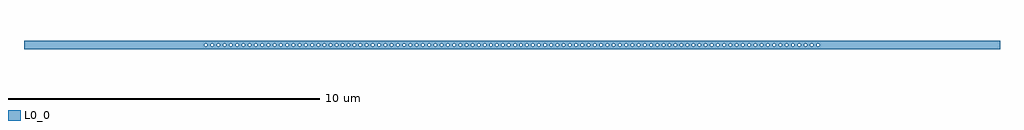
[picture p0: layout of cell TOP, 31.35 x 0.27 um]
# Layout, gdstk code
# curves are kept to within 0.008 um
import gdstk
lib = gdstk.Library(unit=1e-6, precision=1e-09)
def P(c, l, *ps):  # polygons
    for p in ps: c.add(gdstk.Polygon(p, *l))
L0_0 = (0, 0)

top = lib.new_cell('TOP')
P(top, L0_0, [(0,0),(0,0),(0,0),(0,0)],
  [(-8.211,0.048),(-8.197,0.041),(-8.184,0.03),(-8.177,0.016),(-8.175,0.005),(-8.175,0.133),(-15.675,0.133),(-15.675,0.049),(-8.228,0.049)],
  [(-8.175,-0.008),(-8.184,-0.03),(-8.211,-0.048),(-8.257,-0.036),(-8.272,-0.008),(-8.267,0.024),(-8.228,0.049),(-8.429,0.049),(-8.385,0.03),(-8.375,0),(-8.385,-0.03),(-8.429,-0.049),(-8.458,-0.036),(-8.473,-0.008),(-8.468,0.024),(-8.429,0.049),(-8.63,0.049),(-8.586,0.03),(-8.576,0),(-8.586,-0.03),(-8.63,-0.049),(-8.659,-0.036),(-8.674,-0.008),(-8.669,0.024),(-8.63,0.049),(-8.831,0.049),(-8.787,0.03),(-8.777,0),(-8.787,-0.03),(-8.831,-0.049),(-8.86,-0.036),(-8.875,-0.008),(-8.87,0.024),(-8.831,0.049),(-9.032,0.049),(-8.988,0.03),(-8.978,0),(-8.988,-0.03),(-9.032,-0.049),(-9.061,-0.036),(-9.076,-0.008),(-9.071,0.024),(-9.032,0.049),(-9.233,0.049),(-9.189,0.03),(-9.179,0),(-9.189,-0.03),(-9.233,-0.049),(-9.262,-0.036),(-9.277,-0.008),(-9.272,0.024),(-9.233,0.049),(-9.434,0.049),(-9.39,0.03),(-9.38,0),(-9.39,-0.03),(-9.434,-0.049),(-9.463,-0.036),(-9.478,-0.008),(-9.473,0.024),(-9.434,0.049),(-9.635,0.049),(-9.591,0.03),(-9.581,0),(-9.591,-0.03),(-9.635,-0.049),(-9.664,-0.036),(-9.679,-0.008),(-9.674,0.024),(-9.635,0.049),(-9.836,0.049),(-9.792,0.03),(-9.782,0),(-9.792,-0.03),(-9.836,-0.049),(-9.865,-0.036),(-9.88,-0.008),(-9.875,0.024),(-9.836,0.049),(-15.675,0.049),(-15.675,-0.133),(-8.175,-0.133)],
  [(-6.406,0.048),(-6.371,0.016),(-6.371,-0.016),(-6.391,-0.041),(-6.422,-0.049),(-6.451,-0.036),(-6.467,-0.008),(-6.461,0.024),(-6.422,0.049),(-6.622,0.049),(-6.578,0.03),(-6.568,0),(-6.578,-0.03),(-6.622,-0.049),(-6.65,-0.036),(-6.666,-0.008),(-6.66,0.024),(-6.622,0.049),(-6.822,0.049),(-6.778,0.03),(-6.768,0),(-6.778,-0.03),(-6.822,-0.049),(-6.851,-0.036),(-6.866,-0.008),(-6.861,0.024),(-6.822,0.049),(-7.022,0.049),(-6.979,0.03),(-6.969,0),(-6.979,-0.03),(-7.022,-0.049),(-7.051,-0.036),(-7.067,-0.008),(-7.061,0.024),(-7.022,0.049),(-7.223,0.049),(-7.18,0.03),(-7.17,0),(-7.18,-0.03),(-7.223,-0.049),(-7.252,-0.036),(-7.268,-0.008),(-7.262,0.024),(-7.223,0.049),(-7.424,0.049),(-7.381,0.03),(-7.371,0),(-7.381,-0.03),(-7.424,-0.049),(-7.453,-0.036),(-7.469,-0.008),(-7.463,0.024),(-7.424,0.049),(-7.625,0.049),(-7.581,0.03),(-7.571,0),(-7.581,-0.03),(-7.625,-0.049),(-7.654,-0.036),(-7.669,-0.008),(-7.664,0.024),(-7.625,0.049),(-7.826,0.049),(-7.782,0.03),(-7.772,0),(-7.782,-0.03),(-7.826,-0.049),(-7.855,-0.036),(-7.87,-0.008),(-7.865,0.024),(-7.826,0.049),(-8.027,0.049),(-7.983,0.03),(-7.973,0),(-7.983,-0.03),(-8.027,-0.049),(-8.056,-0.036),(-8.071,-0.008),(-8.066,0.024),(-8.027,0.049),(-8.175,0.049),(-8.175,-0.133),(-6.268,-0.133),(-6.268,0.133),(-8.175,0.133),(-8.175,0.049)],
  [(-6.253,0.036),(-6.239,0.046),(-6.224,0.049),(-6.268,0.049),(-6.268,0.008),(-6.263,0.024)],
  [(-6.268,0.133),(-6.268,0.049),(-4.675,0.049),(-4.632,0.03),(-4.622,0),(-4.644,-0.041),(-4.691,-0.046),(-4.714,-0.024),(-4.72,0.008),(-4.704,0.036),(-4.675,0.049),(-4.876,0.049),(-4.833,0.03),(-4.823,0),(-4.833,-0.03),(-4.876,-0.049),(-4.905,-0.036),(-4.921,-0.008),(-4.915,0.024),(-4.876,0.049),(-5.065,0.049),(-5.022,0.03),(-5.012,0),(-5.022,-0.03),(-5.065,-0.049),(-5.094,-0.036),(-5.11,-0.008),(-5.104,0.024),(-5.065,0.049),(-5.255,0.049),(-5.211,0.03),(-5.201,0),(-5.211,-0.03),(-5.255,-0.049),(-5.284,-0.036),(-5.299,-0.008),(-5.294,0.024),(-5.255,0.049),(-5.445,0.049),(-5.402,0.03),(-5.392,0),(-5.402,-0.03),(-5.445,-0.049),(-5.474,-0.036),(-5.49,-0.008),(-5.484,0.024),(-5.445,0.049),(-5.637,0.049),(-5.594,0.03),(-5.584,0),(-5.594,-0.03),(-5.637,-0.049),(-5.666,-0.036),(-5.682,-0.008),(-5.676,0.024),(-5.637,0.049),(-5.831,0.049),(-5.788,0.03),(-5.778,0),(-5.788,-0.03),(-5.831,-0.049),(-5.86,-0.036),(-5.876,-0.008),(-5.87,0.024),(-5.831,0.049),(-6.027,0.049),(-5.983,0.03),(-5.973,0),(-5.983,-0.03),(-6.027,-0.049),(-6.055,-0.036),(-6.071,-0.008),(-6.065,0.024),(-6.027,0.049),(-6.224,0.049),(-6.18,0.03),(-6.171,-0.008),(-6.193,-0.041),(-6.224,-0.049),(-6.253,-0.036),(-6.268,-0.008),(-6.268,-0.133),(-4.503,-0.133),(-4.503,-0.036),(-4.519,-0.008),(-4.503,0.036),(-4.503,0.133)],
  [(-2.649,0.048),(-2.649,0.133),(-4.503,0.133),(-4.503,0.049),(-2.665,0.049)],
  [(-2.649,-0.048),(-2.681,-0.046),(-2.71,-0.008),(-2.704,0.024),(-2.665,0.049),(-2.866,0.049),(-2.823,0.03),(-2.813,0),(-2.823,-0.03),(-2.866,-0.049),(-2.895,-0.036),(-2.911,-0.008),(-2.905,0.024),(-2.866,0.049),(-3.067,0.049),(-3.024,0.03),(-3.014,0),(-3.024,-0.03),(-3.067,-0.049),(-3.096,-0.036),(-3.112,-0.008),(-3.106,0.024),(-3.067,0.049),(-3.268,0.049),(-3.225,0.03),(-3.215,0),(-3.225,-0.03),(-3.268,-0.049),(-3.297,-0.036),(-3.313,-0.008),(-3.307,0.024),(-3.268,0.049),(-3.469,0.049),(-3.426,0.03),(-3.416,0),(-3.426,-0.03),(-3.469,-0.049),(-3.498,-0.036),(-3.514,-0.008),(-3.508,0.024),(-3.469,0.049),(-3.67,0.049),(-3.627,0.03),(-3.617,0),(-3.627,-0.03),(-3.67,-0.049),(-3.699,-0.036),(-3.715,-0.008),(-3.709,0.024),(-3.67,0.049),(-3.871,0.049),(-3.828,0.03),(-3.818,0),(-3.828,-0.03),(-3.871,-0.049),(-3.9,-0.036),(-3.916,-0.008),(-3.91,0.024),(-3.871,0.049),(-4.072,0.049),(-4.029,0.03),(-4.019,0),(-4.029,-0.03),(-4.072,-0.049),(-4.101,-0.036),(-4.117,-0.008),(-4.111,0.024),(-4.072,0.049),(-4.273,0.049),(-4.23,0.03),(-4.22,0),(-4.23,-0.03),(-4.273,-0.049),(-4.302,-0.036),(-4.318,-0.008),(-4.312,0.024),(-4.273,0.049),(-4.474,0.049),(-4.431,0.03),(-4.423,-0.016),(-4.458,-0.048),(-4.503,-0.036),(-4.503,-0.133),(-2.649,-0.133)],
  [(-4.49,0.046),(-4.474,0.049),(-4.503,0.049),(-4.503,0.036)],
  [(-0.855,0.048),(-0.841,0.041),(-0.841,0.133),(-2.649,0.133),(-2.649,0.049),(-0.871,0.049)],
  [(-0.841,-0.041),(-0.887,-0.046),(-0.916,-0.008),(-0.91,0.024),(-0.871,0.049),(-1.067,0.049),(-1.024,0.03),(-1.014,0),(-1.024,-0.03),(-1.067,-0.049),(-1.096,-0.036),(-1.112,-0.008),(-1.106,0.024),(-1.067,0.049),(-1.264,0.049),(-1.221,0.03),(-1.211,0),(-1.221,-0.03),(-1.264,-0.049),(-1.293,-0.036),(-1.309,-0.008),(-1.303,0.024),(-1.264,0.049),(-1.463,0.049),(-1.419,0.03),(-1.409,0),(-1.419,-0.03),(-1.463,-0.049),(-1.492,-0.036),(-1.507,-0.008),(-1.502,0.024),(-1.463,0.049),(-1.662,0.049),(-1.619,0.03),(-1.609,0),(-1.619,-0.03),(-1.662,-0.049),(-1.691,-0.036),(-1.707,-0.008),(-1.701,0.024),(-1.662,0.049),(-1.862,0.049),(-1.819,0.03),(-1.809,0),(-1.819,-0.03),(-1.862,-0.049),(-1.891,-0.036),(-1.907,-0.008),(-1.901,0.024),(-1.862,0.049),(-2.063,0.049),(-2.019,0.03),(-2.009,0),(-2.019,-0.03),(-2.063,-0.049),(-2.092,-0.036),(-2.107,-0.008),(-2.102,0.024),(-2.063,0.049),(-2.264,0.049),(-2.22,0.03),(-2.21,0),(-2.22,-0.03),(-2.264,-0.049),(-2.292,-0.036),(-2.308,-0.008),(-2.302,0.024),(-2.264,0.049),(-2.464,0.049),(-2.421,0.03),(-2.411,0),(-2.421,-0.03),(-2.464,-0.049),(-2.493,-0.036),(-2.509,-0.008),(-2.503,0.024),(-2.464,0.049),(-2.649,0.049),(-2.622,0.03),(-2.612,0),(-2.622,-0.03),(-2.649,-0.048),(-2.649,-0.133),(-0.841,-0.133)],
  [(0.879,0.048),(0.894,0.041),(0.894,0.133),(-0.841,0.133),(-0.841,0.049),(0.863,0.049)],
  [(0.894,-0.041),(0.847,-0.046),(0.818,-0.008),(0.824,0.024),(0.863,0.049),(0.669,0.049),(0.712,0.03),(0.722,0),(0.712,-0.03),(0.669,-0.049),(0.64,-0.036),(0.624,-0.008),(0.63,0.024),(0.669,0.049),(0.477,0.049),(0.52,0.03),(0.53,0),(0.52,-0.03),(0.477,-0.049),(0.448,-0.036),(0.432,-0.008),(0.438,0.024),(0.477,0.049),(0.287,0.049),(0.33,0.03),(0.34,0),(0.33,-0.03),(0.287,-0.049),(0.258,-0.036),(0.242,-0.008),(0.248,0.024),(0.287,0.049),(0.097,0.049),(0.128,0.041),(0.151,0),(0.128,-0.041),(0.097,-0.049),(0.068,-0.036),(0.052,-0.008),(0.058,0.024),(0.097,0.049),(-0.106,0.049),(-0.062,0.03),(-0.052,0),(-0.062,-0.03),(-0.106,-0.049),(-0.135,-0.036),(-0.151,-0.008),(-0.145,0.024),(-0.106,0.049),(-0.295,0.049),(-0.252,0.03),(-0.242,0),(-0.252,-0.03),(-0.295,-0.049),(-0.324,-0.036),(-0.34,-0.008),(-0.334,0.024),(-0.295,0.049),(-0.486,0.049),(-0.442,0.03),(-0.432,0),(-0.442,-0.03),(-0.486,-0.049),(-0.514,-0.036),(-0.53,-0.008),(-0.524,0.024),(-0.486,0.049),(-0.678,0.049),(-0.634,0.03),(-0.624,0),(-0.634,-0.03),(-0.678,-0.049),(-0.706,-0.036),(-0.722,-0.008),(-0.716,0.024),(-0.678,0.049),(-0.841,0.049),(-0.818,0),(-0.841,-0.041),(-0.841,-0.133),(0.894,-0.133)],
  [(2.673,0.048),(2.688,0.041),(2.7,0.03),(2.7,0.133),(0.894,0.133),(0.894,0.049),(2.657,0.049)],
  [(2.7,-0.03),(2.657,-0.049),(2.618,-0.024),(2.618,0.024),(2.657,0.049),(2.456,0.049),(2.499,0.03),(2.509,0),(2.499,-0.03),(2.456,-0.049),(2.427,-0.036),(2.411,-0.008),(2.417,0.024),(2.456,0.049),(2.255,0.049),(2.298,0.03),(2.308,0),(2.298,-0.03),(2.255,-0.049),(2.226,-0.036),(2.21,-0.008),(2.216,0.024),(2.255,0.049),(2.054,0.049),(2.097,0.03),(2.107,0),(2.097,-0.03),(2.054,-0.049),(2.025,-0.036),(2.009,-0.008),(2.015,0.024),(2.054,0.049),(1.854,0.049),(1.897,0.03),(1.907,0),(1.897,-0.03),(1.854,-0.049),(1.825,-0.036),(1.809,-0.008),(1.815,0.024),(1.854,0.049),(1.653,0.049),(1.697,0.03),(1.707,0),(1.697,-0.03),(1.653,-0.049),(1.625,-0.036),(1.609,-0.008),(1.615,0.024),(1.653,0.049),(1.454,0.049),(1.497,0.03),(1.507,0),(1.497,-0.03),(1.454,-0.049),(1.425,-0.036),(1.409,-0.008),(1.415,0.024),(1.454,0.049),(1.256,0.049),(1.299,0.03),(1.309,0),(1.299,-0.03),(1.256,-0.049),(1.227,-0.036),(1.211,-0.008),(1.217,0.024),(1.256,0.049),(1.058,0.049),(1.102,0.03),(1.112,0),(1.102,-0.03),(1.058,-0.049),(1.03,-0.036),(1.014,-0.008),(1.02,0.024),(1.058,0.049),(0.894,0.049),(0.916,0),(0.894,-0.041),(0.894,-0.133),(2.7,-0.133)],
  [(4.281,0.048),(4.308,0.03),(4.318,0),(4.308,-0.03),(4.265,-0.049),(4.236,-0.036),(4.22,-0.008),(4.226,0.024),(4.265,0.049),(4.064,0.049),(4.107,0.03),(4.117,0),(4.107,-0.03),(4.064,-0.049),(4.035,-0.036),(4.019,-0.008),(4.025,0.024),(4.064,0.049),(3.863,0.049),(3.906,0.03),(3.916,0),(3.906,-0.03),(3.863,-0.049),(3.834,-0.036),(3.818,-0.008),(3.824,0.024),(3.863,0.049),(3.662,0.049),(3.705,0.03),(3.715,0),(3.705,-0.03),(3.662,-0.049),(3.633,-0.036),(3.617,-0.008),(3.623,0.024),(3.662,0.049),(3.461,0.049),(3.504,0.03),(3.514,0),(3.504,-0.03),(3.461,-0.049),(3.432,-0.036),(3.416,-0.008),(3.422,0.024),(3.461,0.049),(3.26,0.049),(3.303,0.03),(3.313,0),(3.303,-0.03),(3.26,-0.049),(3.231,-0.036),(3.215,-0.008),(3.221,0.024),(3.26,0.049),(3.059,0.049),(3.102,0.03),(3.112,0),(3.102,-0.03),(3.059,-0.049),(3.03,-0.036),(3.014,-0.008),(3.02,0.024),(3.059,0.049),(2.858,0.049),(2.901,0.03),(2.911,0),(2.901,-0.03),(2.858,-0.049),(2.829,-0.036),(2.813,-0.008),(2.819,0.024),(2.858,0.049),(2.7,0.049),(2.71,0),(2.7,-0.133),(4.466,-0.133),(4.466,-0.049),(4.437,-0.036),(4.421,-0.008),(4.427,0.024),(4.466,0.049),(4.466,0.133),(2.7,0.133),(2.7,0.049)],
  [(6.034,0.048),(6.069,0.016),(6.069,-0.016),(6.049,-0.041),(6.018,-0.049),(5.989,-0.036),(5.973,-0.008),(5.979,0.024),(6.018,0.049),(5.822,0.049),(5.866,0.03),(5.876,0),(5.866,-0.03),(5.822,-0.049),(5.793,-0.036),(5.777,-0.008),(5.783,0.024),(5.822,0.049),(5.628,0.049),(5.672,0.03),(5.682,0),(5.672,-0.03),(5.628,-0.049),(5.6,-0.036),(5.584,-0.008),(5.59,0.024),(5.628,0.049),(5.436,0.049),(5.48,0.03),(5.49,0),(5.48,-0.03),(5.436,-0.049),(5.408,-0.036),(5.392,-0.008),(5.398,0.024),(5.436,0.049),(5.246,0.049),(5.289,0.03),(5.299,0),(5.289,-0.03),(5.246,-0.049),(5.217,-0.036),(5.201,-0.008),(5.207,0.024),(5.246,0.049),(5.057,0.049),(5.1,0.03),(5.11,0),(5.1,-0.03),(5.057,-0.049),(5.028,-0.036),(5.012,-0.008),(5.018,0.024),(5.057,0.049),(4.868,0.049),(4.911,0.03),(4.921,0),(4.911,-0.03),(4.868,-0.049),(4.839,-0.036),(4.823,-0.008),(4.829,0.024),(4.868,0.049),(4.667,0.049),(4.71,0.03),(4.72,0),(4.71,-0.03),(4.667,-0.049),(4.638,-0.036),(4.622,-0.008),(4.628,0.024),(4.667,0.049),(4.466,0.049),(4.509,0.03),(4.519,0),(4.509,-0.03),(4.466,-0.049),(4.466,-0.133),(6.215,-0.133),(6.215,-0.049),(6.186,-0.036),(6.17,-0.008),(6.176,0.024),(6.215,0.049),(6.215,0.133),(4.466,0.133),(4.466,0.049)],
  [(8.034,0.048),(8.034,0.133),(6.215,0.133),(6.215,0.049),(8.018,0.049)],
  [(8.034,-0.048),(8.002,-0.046),(7.973,-0.008),(7.979,0.024),(8.018,0.049),(7.817,0.049),(7.86,0.03),(7.87,0),(7.86,-0.03),(7.817,-0.049),(7.788,-0.036),(7.772,-0.008),(7.778,0.024),(7.817,0.049),(7.616,0.049),(7.659,0.03),(7.669,0),(7.659,-0.03),(7.616,-0.049),(7.587,-0.036),(7.571,-0.008),(7.577,0.024),(7.616,0.049),(7.415,0.049),(7.446,0.041),(7.469,0),(7.446,-0.041),(7.415,-0.049),(7.386,-0.036),(7.37,-0.008),(7.376,0.024),(7.415,0.049),(7.214,0.049),(7.258,0.03),(7.268,0),(7.258,-0.03),(7.214,-0.049),(7.185,-0.036),(7.17,-0.008),(7.175,0.024),(7.214,0.049),(7.014,0.049),(7.057,0.03),(7.067,0),(7.057,-0.03),(7.014,-0.049),(6.985,-0.036),(6.969,-0.008),(6.975,0.024),(7.014,0.049),(6.813,0.049),(6.856,0.03),(6.866,0),(6.856,-0.03),(6.813,-0.049),(6.784,-0.036),(6.768,-0.008),(6.774,0.024),(6.813,0.049),(6.613,0.049),(6.656,0.03),(6.666,0),(6.656,-0.03),(6.613,-0.049),(6.584,-0.036),(6.568,-0.008),(6.574,0.024),(6.613,0.049),(6.413,0.049),(6.457,0.03),(6.467,0),(6.457,-0.03),(6.413,-0.049),(6.385,-0.036),(6.369,-0.008),(6.375,0.024),(6.413,0.049),(6.215,0.049),(6.258,0.03),(6.268,0),(6.258,-0.03),(6.215,-0.049),(6.215,-0.133),(8.034,-0.133)],
  [(8.049,0.041),(8.069,0.016),(8.07,-0.008),(8.174,-0.008),(8.18,0.024),(8.219,0.049),(8.262,0.03),(8.271,-0.008),(8.375,-0.008),(8.381,0.024),(8.42,0.049),(8.463,0.03),(8.472,-0.008),(8.576,-0.008),(8.582,0.024),(8.621,0.049),(8.664,0.03),(8.673,-0.008),(8.777,-0.008),(8.783,0.024),(8.822,0.049),(8.865,0.03),(8.875,0),(8.865,-0.03),(8.822,-0.049),(8.793,-0.036),(8.777,-0.008),(8.673,-0.008),(8.652,-0.041),(8.621,-0.049),(8.592,-0.036),(8.576,-0.008),(8.472,-0.008),(8.451,-0.041),(8.42,-0.049),(8.391,-0.036),(8.375,-0.008),(8.271,-0.008),(8.25,-0.041),(8.219,-0.049),(8.19,-0.036),(8.174,-0.008),(8.07,-0.008),(8.061,-0.03),(8.034,-0.048),(8.034,-0.133),(8.994,-0.133),(8.994,-0.036),(8.978,-0.008),(8.994,0.036),(8.994,0.133),(8.034,0.133),(8.034,0.048)],
  [(9.023,0.049),(9.066,0.03),(9.075,-0.008),(9.179,-0.008),(9.185,0.024),(9.224,0.049),(9.267,0.03),(9.276,-0.008),(9.38,-0.008),(9.386,0.024),(9.425,0.049),(9.468,0.03),(9.477,-0.008),(9.581,-0.008),(9.587,0.024),(9.626,0.049),(9.669,0.03),(9.678,-0.008),(9.782,-0.008),(9.798,0.036),(9.843,0.048),(9.871,0.03),(9.878,-0.016),(9.858,-0.041),(9.827,-0.049),(9.798,-0.036),(9.782,-0.008),(9.678,-0.008),(9.657,-0.041),(9.626,-0.049),(9.597,-0.036),(9.581,-0.008),(9.477,-0.008),(9.456,-0.041),(9.425,-0.049),(9.396,-0.036),(9.38,-0.008),(9.276,-0.008),(9.255,-0.041),(9.224,-0.049),(9.195,-0.036),(9.179,-0.008),(9.075,-0.008),(9.066,-0.03),(9.039,-0.048),(8.994,-0.036),(8.994,-0.133),(15.675,-0.133),(15.675,0.133),(8.994,0.133),(8.994,0.036)])

lib.write_gds('TOP.gds')
